###############################################################
#  Generated by:      Cadence Innovus 20.13-s083_1
#  OS:                Linux x86_64(Host ID rice-503-20-north)
#  Generated on:      Tue May 17 14:51:37 2022
#  Design:            bgr_top
#  Command:           write_lef_abstract -specifyTopLayer 6 -PGPinLayers {5 6} -noCutObs -stripePin results/bgr_top.lef
###############################################################

VERSION 5.8 ;

BUSBITCHARS "[]" ;
DIVIDERCHAR "/" ;

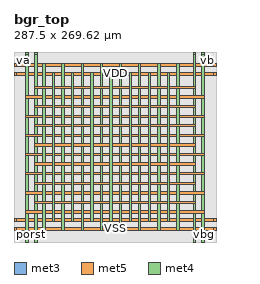
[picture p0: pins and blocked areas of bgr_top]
MACRO bgr_top
  CLASS BLOCK ;
  SIZE 287.500000 BY 269.620000 ;
  FOREIGN bgr_top 0.000000 0.000000 ;
  ORIGIN 0 0 ;
  SYMMETRY X Y R90 ;
  PIN porst
    DIRECTION INPUT ;
    USE SIGNAL ;
    PORT
      LAYER met3 ;
        RECT 0.000000 0.560000 0.800000 0.860000 ;
    END
  END porst
  PIN va
    DIRECTION OUTPUT ;
    USE SIGNAL ;
    ANTENNADIFFAREA 82.639 LAYER met3  ;
    ANTENNAPARTIALMETALAREA 14.1024 LAYER met3  ;
    ANTENNAPARTIALMETALSIDEAREA 75.208 LAYER met3  ;
    PORT
      LAYER met3 ;
        RECT 0.000000 268.960000 0.800000 269.260000 ;
    END
  END va
  PIN vb
    DIRECTION OUTPUT ;
    USE SIGNAL ;
    ANTENNADIFFAREA 57.9855 LAYER met3  ;
    ANTENNAPARTIALMETALAREA 15.2064 LAYER met3  ;
    ANTENNAPARTIALMETALSIDEAREA 81.096 LAYER met3  ;
    PORT
      LAYER met3 ;
        RECT 286.700000 268.960000 287.500000 269.260000 ;
    END
  END vb
  PIN vbg
    DIRECTION OUTPUT ;
    USE SIGNAL ;
    ANTENNADIFFAREA 57.9855 LAYER met3  ;
    ANTENNAPARTIALMETALAREA 19.7424 LAYER met3  ;
    ANTENNAPARTIALMETALSIDEAREA 105.768 LAYER met3  ;
    PORT
      LAYER met3 ;
        RECT 286.700000 0.560000 287.500000 0.860000 ;
    END
  END vbg
  PIN VDD
    DIRECTION INOUT ;
    USE POWER ;
    PORT
      LAYER met5 ;
        RECT 283.500000 236.800000 287.500000 240.800000 ;
    END
    PORT
      LAYER met5 ;
        RECT 0.000000 236.800000 4.000000 240.800000 ;
    END
    PORT
      LAYER met5 ;
        RECT 283.500000 28.800000 287.500000 32.800000 ;
    END
    PORT
      LAYER met5 ;
        RECT 0.000000 28.800000 4.000000 32.800000 ;
    END
    PORT
      LAYER met4 ;
        RECT 254.250000 265.620000 258.250000 269.620000 ;
    END
    PORT
      LAYER met4 ;
        RECT 254.250000 0.000000 258.250000 4.000000 ;
    END
    PORT
      LAYER met4 ;
        RECT 28.940000 265.620000 32.940000 269.620000 ;
    END
    PORT
      LAYER met4 ;
        RECT 28.940000 0.000000 32.940000 4.000000 ;
    END

# P/G power stripe data as pin
    PORT
      LAYER met4 ;
        RECT 136.000000 28.800000 139.360000 240.800000 ;
        RECT 108.800000 28.800000 112.160000 240.800000 ;
        RECT 81.600000 28.800000 84.960000 240.800000 ;
        RECT 54.400000 28.800000 57.760000 240.800000 ;
        RECT 28.940000 0.000000 32.940000 269.620000 ;
        RECT 217.600000 28.800000 220.960000 240.800000 ;
        RECT 190.400000 28.800000 193.760000 240.800000 ;
        RECT 163.200000 28.800000 166.560000 240.800000 ;
        RECT 254.250000 0.000000 258.250000 269.620000 ;
      LAYER met5 ;
        RECT 28.940000 108.800000 258.250000 112.160000 ;
        RECT 28.940000 81.600000 258.250000 84.960000 ;
        RECT 28.940000 54.400000 258.250000 57.760000 ;
        RECT 0.000000 28.800000 287.500000 32.800000 ;
        RECT 28.940000 217.600000 258.250000 220.960000 ;
        RECT 28.940000 190.400000 258.250000 193.760000 ;
        RECT 28.940000 163.200000 258.250000 166.560000 ;
        RECT 28.940000 136.000000 258.250000 139.360000 ;
        RECT 0.000000 236.800000 287.500000 240.800000 ;
    END
# end of P/G power stripe data as pin

  END VDD
  PIN VSS
    DIRECTION INOUT ;
    USE GROUND ;
    PORT
      LAYER met5 ;
        RECT 283.500000 248.800000 287.500000 252.800000 ;
    END
    PORT
      LAYER met5 ;
        RECT 0.000000 248.800000 4.000000 252.800000 ;
    END
    PORT
      LAYER met5 ;
        RECT 283.500000 16.800000 287.500000 20.800000 ;
    END
    PORT
      LAYER met5 ;
        RECT 0.000000 16.800000 4.000000 20.800000 ;
    END
    PORT
      LAYER met4 ;
        RECT 266.250000 265.620000 270.250000 269.620000 ;
    END
    PORT
      LAYER met4 ;
        RECT 266.250000 0.000000 270.250000 4.000000 ;
    END
    PORT
      LAYER met4 ;
        RECT 16.940000 265.620000 20.940000 269.620000 ;
    END
    PORT
      LAYER met4 ;
        RECT 16.940000 0.000000 20.940000 4.000000 ;
    END

# P/G power stripe data as pin
    PORT
      LAYER met4 ;
        RECT 16.940000 0.000000 20.940000 269.620000 ;
        RECT 40.800000 16.800000 44.160000 252.800000 ;
        RECT 68.000000 16.800000 71.360000 252.800000 ;
        RECT 95.200000 16.800000 98.560000 252.800000 ;
        RECT 122.400000 16.800000 125.760000 252.800000 ;
        RECT 266.250000 0.000000 270.250000 269.620000 ;
        RECT 149.600000 16.800000 152.960000 252.800000 ;
        RECT 176.800000 16.800000 180.160000 252.800000 ;
        RECT 204.000000 16.800000 207.360000 252.800000 ;
        RECT 231.200000 16.800000 234.560000 252.800000 ;
      LAYER met5 ;
        RECT 0.000000 16.800000 287.500000 20.800000 ;
        RECT 16.940000 40.800000 270.250000 44.160000 ;
        RECT 16.940000 68.000000 270.250000 71.360000 ;
        RECT 16.940000 95.200000 270.250000 98.560000 ;
        RECT 16.940000 122.400000 270.250000 125.760000 ;
        RECT 0.000000 248.800000 287.500000 252.800000 ;
        RECT 16.940000 149.600000 270.250000 152.960000 ;
        RECT 16.940000 176.800000 270.250000 180.160000 ;
        RECT 16.940000 204.000000 270.250000 207.360000 ;
    END
# end of P/G power stripe data as pin

  END VSS
  OBS
    LAYER li1 ;
      RECT 0.000000 0.000000 287.500000 269.620000 ;
    LAYER met1 ;
      RECT 0.000000 0.000000 287.500000 269.620000 ;
    LAYER met2 ;
      RECT 0.000000 0.000000 287.500000 269.620000 ;
    LAYER met3 ;
      RECT 0.000000 0.000000 287.500000 269.620000 ;
    LAYER met4 ;
      RECT 0.000000 0.000000 287.500000 269.620000 ;
    LAYER met5 ;
      RECT 0.000000 0.000000 287.500000 269.620000 ;
  END
END bgr_top

END LIBRARY
